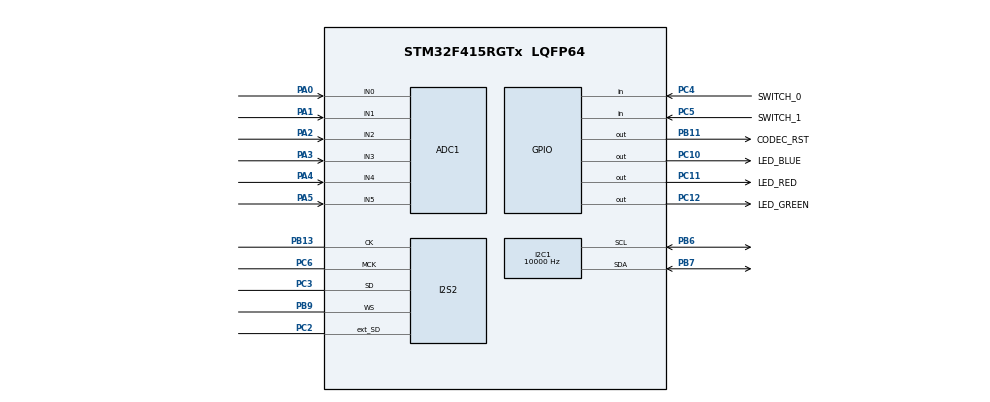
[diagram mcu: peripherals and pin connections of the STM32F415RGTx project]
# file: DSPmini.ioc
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ADC1.Channel-0\#ChannelRegularConversion=ADC_CHANNEL_0
ADC1.Channel-10\#ChannelRegularConversion=ADC_CHANNEL_5
ADC1.Channel-6\#ChannelRegularConversion=ADC_CHANNEL_1
ADC1.Channel-7\#ChannelRegularConversion=ADC_CHANNEL_2
ADC1.Channel-8\#ChannelRegularConversion=ADC_CHANNEL_3
ADC1.Channel-9\#ChannelRegularConversion=ADC_CHANNEL_4
ADC1.ClockPrescaler=ADC_CLOCK_SYNC_PCLK_DIV8
ADC1.ContinuousConvMode=DISABLE
ADC1.DMAContinuousRequests=ENABLE
ADC1.DiscontinuousConvMode=DISABLE
ADC1.EOCSelection=ADC_EOC_SEQ_CONV
ADC1.ExternalTrigConv=ADC_EXTERNALTRIGCONV_T2_TRGO
ADC1.InjNumberOfConversion=0
ADC1.NbrOfConversion=6
ADC1.NbrOfConversionFlag=1
ADC1.Rank-0\#ChannelRegularConversion=1
ADC1.Rank-10\#ChannelRegularConversion=6
ADC1.Rank-6\#ChannelRegularConversion=2
ADC1.Rank-7\#ChannelRegularConversion=3
ADC1.Rank-8\#ChannelRegularConversion=4
ADC1.Rank-9\#ChannelRegularConversion=5
ADC1.SamplingTime-0\#ChannelRegularConversion=ADC_SAMPLETIME_84CYCLES
ADC1.SamplingTime-10\#ChannelRegularConversion=ADC_SAMPLETIME_84CYCLES
ADC1.SamplingTime-6\#ChannelRegularConversion=ADC_SAMPLETIME_84CYCLES
ADC1.SamplingTime-7\#ChannelRegularConversion=ADC_SAMPLETIME_84CYCLES
ADC1.SamplingTime-8\#ChannelRegularConversion=ADC_SAMPLETIME_84CYCLES
ADC1.SamplingTime-9\#ChannelRegularConversion=ADC_SAMPLETIME_84CYCLES
ADC1.ScanConvMode=ENABLE
ADC1.master=1
Dma.ADC1.0.Direction=DMA_PERIPH_TO_MEMORY
Dma.ADC1.0.FIFOMode=DMA_FIFOMODE_DISABLE
Dma.ADC1.0.Instance=DMA2_Stream0
Dma.ADC1.0.MemDataAlignment=DMA_MDATAALIGN_HALFWORD
Dma.ADC1.0.MemInc=DMA_MINC_ENABLE
Dma.ADC1.0.Mode=DMA_CIRCULAR
Dma.ADC1.0.PeriphDataAlignment=DMA_PDATAALIGN_HALFWORD
Dma.ADC1.0.PeriphInc=DMA_PINC_DISABLE
Dma.ADC1.0.Priority=DMA_PRIORITY_MEDIUM
Dma.I2S2_EXT_RX.2.Direction=DMA_PERIPH_TO_MEMORY
Dma.I2S2_EXT_RX.2.FIFOMode=DMA_FIFOMODE_DISABLE
Dma.I2S2_EXT_RX.2.Instance=DMA1_Stream3
Dma.I2S2_EXT_RX.2.MemDataAlignment=DMA_MDATAALIGN_HALFWORD
Dma.I2S2_EXT_RX.2.MemInc=DMA_MINC_ENABLE
Dma.I2S2_EXT_RX.2.Mode=DMA_CIRCULAR
Dma.I2S2_EXT_RX.2.PeriphDataAlignment=DMA_PDATAALIGN_HALFWORD
Dma.I2S2_EXT_RX.2.PeriphInc=DMA_PINC_DISABLE
Dma.I2S2_EXT_RX.2.Priority=DMA_PRIORITY_VERY_HIGH
Dma.Request0=ADC1
Dma.Request1=SPI2_TX
Dma.Request2=I2S2_EXT_RX
Dma.SPI2_TX.1.Direction=DMA_MEMORY_TO_PERIPH
Dma.SPI2_TX.1.FIFOMode=DMA_FIFOMODE_DISABLE
Dma.SPI2_TX.1.Instance=DMA1_Stream4
Dma.SPI2_TX.1.MemDataAlignment=DMA_MDATAALIGN_HALFWORD
Dma.SPI2_TX.1.MemInc=DMA_MINC_ENABLE
Dma.SPI2_TX.1.Mode=DMA_CIRCULAR
Dma.SPI2_TX.1.PeriphDataAlignment=DMA_PDATAALIGN_HALFWORD
Dma.SPI2_TX.1.PeriphInc=DMA_PINC_DISABLE
Dma.SPI2_TX.1.Priority=DMA_PRIORITY_VERY_HIGH
I2C1.ClockSpeed=10000
I2S2.AudioFreq=I2S_AUDIOFREQ_48K
I2S2.ErrorAudioFreq=-2.34 %
I2S2.FullDuplexMode=I2S_FULLDUPLEXMODE_ENABLE
I2S2.Instance=SPI$Index
I2S2.RealAudioFreq=46.875 KHz
I2S2.VirtualMode=I2S_MODE_MASTER
Mcu.Family=STM32F4
Mcu.Name=STM32F415RGTx
Mcu.Package=LQFP64
NVIC.DMA1_Stream3_IRQn=true\:0\:0\:false\:false\:true\:false\:true\:true
NVIC.DMA1_Stream4_IRQn=true\:0\:0\:false\:false\:true\:false\:true\:true
NVIC.DMA2_Stream0_IRQn=true\:0\:0\:false\:false\:true\:false\:true\:true
NVIC.PriorityGroup=NVIC_PRIORITYGROUP_4
NVIC.TIM3_IRQn=true\:0\:0\:false\:false\:true\:true\:true\:true
PA0-WKUP.Signal=ADCx_IN0
PA1.Signal=ADCx_IN1
PA13.Mode=Serial_Wire
PA13.Signal=SYS_JTMS-SWDIO
PA14.Mode=Serial_Wire
PA14.Signal=SYS_JTCK-SWCLK
PA2.Signal=ADCx_IN2
PA3.Signal=ADCx_IN3
PA4.Signal=ADCx_IN4
PA5.Signal=ADCx_IN5
PB11.GPIO_Label=CODEC_RST
PB11.Signal=GPIO_Output
PB13.Mode=Full_Duplex_Master
PB13.Signal=I2S2_CK
PB6.Mode=I2C
PB6.Signal=I2C1_SCL
PB7.Mode=I2C
PB7.Signal=I2C1_SDA
PB9.Mode=Full_Duplex_Master
PB9.Signal=I2S2_WS
PC10.GPIO_Label=LED_BLUE
PC10.Signal=GPIO_Output
PC11.GPIO_Label=LED_RED
PC11.Signal=GPIO_Output
PC12.GPIO_Label=LED_GREEN
PC12.Signal=GPIO_Output
PC2.Mode=Full_Duplex_Master
PC2.Signal=I2S2_ext_SD
PC3.Mode=Full_Duplex_Master
PC3.Signal=I2S2_SD
PC4.GPIO_Label=SWITCH_0
PC4.Signal=GPIO_Input
PC5.GPIO_Label=SWITCH_1
PC5.Signal=GPIO_Input
PC6.Mode=Master_Clock_Activated
PC6.Signal=I2S2_MCK
ProjectManager.HeapSize=0x200
ProjectManager.StackSize=0x400
ProjectManager.TargetToolchain=STM32CubeIDE
RCC.AHBFreq_Value=16000000
RCC.APB1Freq_Value=16000000
RCC.APB2Freq_Value=16000000
RCC.CortexFreq_Value=16000000
RCC.HSE_VALUE=25000000
RCC.HSI_VALUE=16000000
RCC.LSE_VALUE=32768
RCC.SYSCLKFreq_VALUE=16000000
RCC.VCOOutputFreq_Value=192000000
SH.ADCx_IN0.0=ADC1_IN0,IN0
SH.ADCx_IN1.0=ADC1_IN1,IN1
SH.ADCx_IN2.0=ADC1_IN2,IN2
SH.ADCx_IN3.0=ADC1_IN3,IN3
SH.ADCx_IN4.0=ADC1_IN4,IN4
SH.ADCx_IN5.0=ADC1_IN5,IN5
TIM2.AutoReloadPreload=TIM_AUTORELOAD_PRELOAD_ENABLE
TIM2.Period=49999
TIM2.Prescaler=31
TIM2.TIM_MasterOutputTrigger=TIM_TRGO_UPDATE
TIM3.TIM_MasterOutputTrigger=TIM_TRGO_UPDATE
VP_TIM2_VS_ClockSourceINT.Mode=Internal
VP_TIM3_VS_ClockSourceINT.Mode=Internal
board=custom

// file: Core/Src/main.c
/* USER CODE BEGIN Header */
/**
  ******************************************************************************
  * @file           : main.c
  * @brief          : Main program body
  ******************************************************************************
  * @attention
  *
  * Copyright (c) 2024 STMicroelectronics.
  * All rights reserved.
  *
  * This software is licensed under terms that can be found in the LICENSE file
  * in the root directory of this software component.
  * If no LICENSE file comes with this software, it is provided AS-IS.
  *
  ******************************************************************************
  */
/* USER CODE END Header */
#include "main.h"

/* USER CODE BEGIN Includes */
#include "codec.h"
#include "IIR_PeakingFilter.h"
/* USER CODE END Includes */

/* USER CODE BEGIN PD */
#define NUM_ADC_CHANNELS 	6
#define AUDIO_BUFFER_SIZE	64

#define SAMPLE_RATE_HZ		46875.0f	//will change when osc is fitted to board

#define UINT16_TO_FLOAT 0.00001525878f
#define INT16_TO_FLOAT 0.00003051757f
#define FLOAT_TO_INT16 32768.0f

#define BASS_EQ_FREQ	150.0f
#define MID_EQ_FREQ		450.0f
#define HIGH_EQ_FREQ	5000.0f
/* USER CODE END PD */

ADC_HandleTypeDef hadc1;
DMA_HandleTypeDef hdma_adc1;

I2C_HandleTypeDef hi2c1;

I2S_HandleTypeDef hi2s2;
DMA_HandleTypeDef hdma_spi2_tx;
DMA_HandleTypeDef hdma_i2s2_ext_rx;

TIM_HandleTypeDef htim2;
TIM_HandleTypeDef htim3;

/* USER CODE BEGIN PV */

uint16_t adcData[NUM_ADC_CHANNELS];	//buffer for the ADC data from the ADC used to read the potentiometers

static int16_t codecInData[AUDIO_BUFFER_SIZE];	//buffers to deal with the in/out of the codec
static int16_t codecOutData[AUDIO_BUFFER_SIZE];

volatile uint8_t audioDataReadyFlag = 0;
volatile uint8_t audio_update_lockout_flag = 0;

static volatile int16_t *codecInBuff_p;	//pointers to help handle the double buffering (read half and process the other half at the same time) of the CODEC data
static volatile int16_t *codecOutBuff_p;
//structure to hold all the ADC values from the pots
struct potentiometers
{
	uint16_t pot1;
	uint16_t pot2;
	uint16_t pot3;
	uint16_t pot4;
	uint16_t pot5;
	uint16_t pot6;
}pots;

IIR_peakingFilter bass_filter;
IIR_peakingFilter mid_filter;
IIR_peakingFilter high_filter;
/* USER CODE END PV */

void SystemClock_Config(void);
static void MX_GPIO_Init(void);
static void MX_DMA_Init(void);
static void MX_ADC1_Init(void);
static void MX_I2C1_Init(void);
static void MX_I2S2_Init(void);
static void MX_TIM2_Init(void);
static void MX_TIM3_Init(void);
/* USER CODE BEGIN PFP */
void update_filter_settings(uint16_t q_pot, uint16_t boostCut_pot, IIR_peakingFilter *filt, float centre_freq);
/* USER CODE END PFP */

/* USER CODE BEGIN 0 */

//this function is called every time an ADC conversion is complete
void HAL_ADC_ConvCpltCallback(ADC_HandleTypeDef *hadc)
{
	//HAL_GPIO_TogglePin(LED_GREEN_GPIO_Port, LED_GREEN_Pin);

	//unload the array into our structure for easier handling
	pots.pot1 = adcData[0];
	pots.pot2 = adcData[1];
	pots.pot3 = adcData[4];
	pots.pot4 = adcData[5];
	pots.pot5 = adcData[2];
	pots.pot6 = adcData[3];

	update_filter_settings(pots.pot1, pots.pot2, &bass_filter, BASS_EQ_FREQ);
	update_filter_settings(pots.pot3, pots.pot4, &mid_filter, MID_EQ_FREQ);
	update_filter_settings(pots.pot5, pots.pot6, &high_filter, HIGH_EQ_FREQ);
}

void update_filter_settings(uint16_t q_pot, uint16_t boostCut_pot, IIR_peakingFilter *filt, float centre_freq)
{
	//convert pot values to something in range for our filters
	//max ADC = 4096
	//205 (approx) for a 20 bit scaling
	float Q, boostCut;

	Q = q_pot / 205;
	boostCut = boostCut_pot / 205;

	if(!audio_update_lockout_flag)
	{
		IIR_peakingFilter_setParams(filt, centre_freq, Q, boostCut);
	}

}

//function is called when I2S data is half complete, so align the pointers to the first half of the buffers
void HAL_I2SEx_TxRxHalfCpltCallback(I2S_HandleTypeDef *hi2s)
{
	codecInBuff_p = &codecInData[0];
	codecOutBuff_p = &codecOutData[0];

	audioDataReadyFlag = 1;
}

//function is called when I2S data is complete, so align the pointers to the second half of the buffers
void HAL_I2SEx_TxRxCpltCallback(I2S_HandleTypeDef *hi2s)
{
	codecInBuff_p = &codecInData[AUDIO_BUFFER_SIZE/2];
	codecOutBuff_p = &codecOutData[AUDIO_BUFFER_SIZE/2];

	audioDataReadyFlag = 1;
}

void processData(void)
{
	static float leftIn, leftOut; //, rightIn, rightOut;

	audio_update_lockout_flag = 1;

	for(uint8_t n = 0; n < (AUDIO_BUFFER_SIZE/2) - 1; n += 2)
	{

	//	codecOutBuff_p[n] = codecInBuff_p[n];	//debug
		//left channel data
		leftIn = INT16_TO_FLOAT * ((float) codecInBuff_p[n]);

		if(leftIn > 1.0f)
		{
			leftIn -= 2.0f;	//make sure data is within 1/-1
		}

		//modify the data here
		leftOut = IIR_peakingFilter_update(&bass_filter, leftIn);
		leftOut = IIR_peakingFilter_update(&mid_filter, leftOut);
	//	leftOut = IIR_peakingFilter_update(&high_filter, leftOut);
		//leftOut = leftIn; //debug

		//convert back to signed int and transfer to DAC (via pointer)
		codecOutBuff_p[n] =  (int16_t) (FLOAT_TO_INT16 * leftOut);

		//////////////////////
		//right channel data (not used in current hardware)
	/*	rightIn = (float)codecInBuff_p[n+1];

		if(rightIn > 1.0f)
		{
			rightIn -= 2.0f;	//make sure data is within 1/-1
		}

		//modify the data here
		rightOut = rightIn;

		//convert back to signed int and transfer to DAC (via pointer)
		codecOutBuff_p[n] = (int16_t) rightOut;
*/
	}

	audio_update_lockout_flag = 0;
	audioDataReadyFlag = 0;
}

/* USER CODE END 0 */

int main(void)
{

  /* MCU Configuration--------------------------------------------------------*/

  /* Reset of all peripherals, Initializes the Flash interface and the Systick. */
  HAL_Init();

  /* Configure the system clock */
  SystemClock_Config();

  /* Initialize all configured peripherals */
  MX_GPIO_Init();
  MX_DMA_Init();
  MX_ADC1_Init();
  MX_I2C1_Init();
  MX_I2S2_Init();
  MX_TIM2_Init();
  MX_TIM3_Init();
  /* USER CODE BEGIN 2 */

  HAL_ADC_Start_DMA(&hadc1, (uint32_t *) adcData, NUM_ADC_CHANNELS); 	//start the ADC and link it with the DMA
  HAL_TIM_Base_Start(&htim2); 											//start timer 2 which triggers the ADC
  HAL_I2SEx_TransmitReceive_DMA(&hi2s2, (uint16_t *) codecOutData, (uint16_t *) codecInData, AUDIO_BUFFER_SIZE);
  codec_hardware_reset_pin_clear();
  HAL_Delay(50);
  codec_configure(&hi2c1);
  IIR_peakingFilter_init(&bass_filter, SAMPLE_RATE_HZ);		//initialise bass frequency peaking filter
  IIR_peakingFilter_init(&mid_filter, SAMPLE_RATE_HZ);
  IIR_peakingFilter_init(&high_filter, SAMPLE_RATE_HZ);
  /* USER CODE END 2 */

  /* Infinite loop */
  /* USER CODE BEGIN WHILE */
  while (1)
  {
	  if(audioDataReadyFlag)
	  {
		  processData();
	  }
/*	  if(HAL_GPIO_ReadPin(GPIOC, GPIO_PIN_4))		//switch 0
	  {
		  HAL_GPIO_TogglePin(GPIOC, GPIO_PIN_10);	//Blue
		  HAL_GPIO_TogglePin(GPIOC, GPIO_PIN_11);	//Red
		  HAL_Delay(500);
	  }

	  if(HAL_GPIO_ReadPin(SWITCH_1_GPIO_Port, SWITCH_1_Pin))
	  {
		  HAL_GPIO_TogglePin(LED_GREEN_GPIO_Port, LED_GREEN_Pin);
		  HAL_Delay(500);
	  }
*/
    /* USER CODE END WHILE */

  }
}

void SystemClock_Config(void)
{
  RCC_OscInitTypeDef RCC_OscInitStruct = {0};
  RCC_ClkInitTypeDef RCC_ClkInitStruct = {0};

  /** Configure the main internal regulator output voltage
  */
  __HAL_RCC_PWR_CLK_ENABLE();
  __HAL_PWR_VOLTAGESCALING_CONFIG(PWR_REGULATOR_VOLTAGE_SCALE1);

  /** Initializes the RCC Oscillators according to the specified parameters
  * in the RCC_OscInitTypeDef structure.
  */
  RCC_OscInitStruct.OscillatorType = RCC_OSCILLATORTYPE_HSI;
  RCC_OscInitStruct.HSIState = RCC_HSI_ON;
  RCC_OscInitStruct.HSICalibrationValue = RCC_HSICALIBRATION_DEFAULT;
  RCC_OscInitStruct.PLL.PLLState = RCC_PLL_ON;
  RCC_OscInitStruct.PLL.PLLSource = RCC_PLLSOURCE_HSI;
  RCC_OscInitStruct.PLL.PLLM = 16;
  RCC_OscInitStruct.PLL.PLLN = 192;
  RCC_OscInitStruct.PLL.PLLP = RCC_PLLP_DIV2;
  RCC_OscInitStruct.PLL.PLLQ = 4;
  if (HAL_RCC_OscConfig(&RCC_OscInitStruct) != HAL_OK)
  {
    Error_Handler();
  }

  /** Initializes the CPU, AHB and APB buses clocks
  */
  RCC_ClkInitStruct.ClockType = RCC_CLOCKTYPE_HCLK|RCC_CLOCKTYPE_SYSCLK
                              |RCC_CLOCKTYPE_PCLK1|RCC_CLOCKTYPE_PCLK2;
  RCC_ClkInitStruct.SYSCLKSource = RCC_SYSCLKSOURCE_PLLCLK;
  RCC_ClkInitStruct.AHBCLKDivider = RCC_SYSCLK_DIV1;
  RCC_ClkInitStruct.APB1CLKDivider = RCC_HCLK_DIV4;
  RCC_ClkInitStruct.APB2CLKDivider = RCC_HCLK_DIV8;

  if (HAL_RCC_ClockConfig(&RCC_ClkInitStruct, FLASH_LATENCY_3) != HAL_OK)
  {
    Error_Handler();
  }
}

static void MX_ADC1_Init(void)
{

  ADC_ChannelConfTypeDef sConfig = {0};

  /** Configure the global features of the ADC (Clock, Resolution, Data Alignment and number of conversion)
  */
  hadc1.Instance = ADC1;
  hadc1.Init.ClockPrescaler = ADC_CLOCK_SYNC_PCLK_DIV8;
  hadc1.Init.Resolution = ADC_RESOLUTION_12B;
  hadc1.Init.ScanConvMode = ENABLE;
  hadc1.Init.ContinuousConvMode = DISABLE;
  hadc1.Init.DiscontinuousConvMode = DISABLE;
  hadc1.Init.ExternalTrigConvEdge = ADC_EXTERNALTRIGCONVEDGE_RISING;
  hadc1.Init.ExternalTrigConv = ADC_EXTERNALTRIGCONV_T2_TRGO;
  hadc1.Init.DataAlign = ADC_DATAALIGN_RIGHT;
  hadc1.Init.NbrOfConversion = 6;
  hadc1.Init.DMAContinuousRequests = ENABLE;
  hadc1.Init.EOCSelection = ADC_EOC_SEQ_CONV;
  if (HAL_ADC_Init(&hadc1) != HAL_OK)
  {
    Error_Handler();
  }

  /** Configure for the selected ADC regular channel its corresponding rank in the sequencer and its sample time.
  */
  sConfig.Channel = ADC_CHANNEL_0;
  sConfig.Rank = 1;
  sConfig.SamplingTime = ADC_SAMPLETIME_84CYCLES;
  if (HAL_ADC_ConfigChannel(&hadc1, &sConfig) != HAL_OK)
  {
    Error_Handler();
  }

  /** Configure for the selected ADC regular channel its corresponding rank in the sequencer and its sample time.
  */
  sConfig.Channel = ADC_CHANNEL_1;
  sConfig.Rank = 2;
  if (HAL_ADC_ConfigChannel(&hadc1, &sConfig) != HAL_OK)
  {
    Error_Handler();
  }

  /** Configure for the selected ADC regular channel its corresponding rank in the sequencer and its sample time.
  */
  sConfig.Channel = ADC_CHANNEL_2;
  sConfig.Rank = 3;
  if (HAL_ADC_ConfigChannel(&hadc1, &sConfig) != HAL_OK)
  {
    Error_Handler();
  }

  /** Configure for the selected ADC regular channel its corresponding rank in the sequencer and its sample time.
  */
  sConfig.Channel = ADC_CHANNEL_3;
  sConfig.Rank = 4;
  if (HAL_ADC_ConfigChannel(&hadc1, &sConfig) != HAL_OK)
  {
    Error_Handler();
  }

  /** Configure for the selected ADC regular channel its corresponding rank in the sequencer and its sample time.
  */
  sConfig.Channel = ADC_CHANNEL_4;
  sConfig.Rank = 5;
  if (HAL_ADC_ConfigChannel(&hadc1, &sConfig) != HAL_OK)
  {
    Error_Handler();
  }

  /** Configure for the selected ADC regular channel its corresponding rank in the sequencer and its sample time.
  */
  sConfig.Channel = ADC_CHANNEL_5;
  sConfig.Rank = 6;
  if (HAL_ADC_ConfigChannel(&hadc1, &sConfig) != HAL_OK)
  {
    Error_Handler();
  }

}

static void MX_I2C1_Init(void)
{

  hi2c1.Instance = I2C1;
  hi2c1.Init.ClockSpeed = 10000;
  hi2c1.Init.DutyCycle = I2C_DUTYCYCLE_2;
  hi2c1.Init.OwnAddress1 = 0;
  hi2c1.Init.AddressingMode = I2C_ADDRESSINGMODE_7BIT;
  hi2c1.Init.DualAddressMode = I2C_DUALADDRESS_DISABLE;
  hi2c1.Init.OwnAddress2 = 0;
  hi2c1.Init.GeneralCallMode = I2C_GENERALCALL_DISABLE;
  hi2c1.Init.NoStretchMode = I2C_NOSTRETCH_DISABLE;
  if (HAL_I2C_Init(&hi2c1) != HAL_OK)
  {
    Error_Handler();
  }

}

static void MX_I2S2_Init(void)
{

  hi2s2.Instance = SPI2;
  hi2s2.Init.Mode = I2S_MODE_MASTER_TX;
  hi2s2.Init.Standard = I2S_STANDARD_PHILIPS;
  hi2s2.Init.DataFormat = I2S_DATAFORMAT_16B;
  hi2s2.Init.MCLKOutput = I2S_MCLKOUTPUT_ENABLE;
  hi2s2.Init.AudioFreq = I2S_AUDIOFREQ_48K;
  hi2s2.Init.CPOL = I2S_CPOL_LOW;
  hi2s2.Init.ClockSource = I2S_CLOCK_PLL;
  hi2s2.Init.FullDuplexMode = I2S_FULLDUPLEXMODE_ENABLE;
  if (HAL_I2S_Init(&hi2s2) != HAL_OK)
  {
    Error_Handler();
  }

}

static void MX_TIM2_Init(void)
{

  TIM_ClockConfigTypeDef sClockSourceConfig = {0};
  TIM_MasterConfigTypeDef sMasterConfig = {0};

  htim2.Instance = TIM2;
  htim2.Init.Prescaler = 31;
  htim2.Init.CounterMode = TIM_COUNTERMODE_UP;
  htim2.Init.Period = 49999;
  htim2.Init.ClockDivision = TIM_CLOCKDIVISION_DIV1;
  htim2.Init.AutoReloadPreload = TIM_AUTORELOAD_PRELOAD_ENABLE;
  if (HAL_TIM_Base_Init(&htim2) != HAL_OK)
  {
    Error_Handler();
  }
  sClockSourceConfig.ClockSource = TIM_CLOCKSOURCE_INTERNAL;
  if (HAL_TIM_ConfigClockSource(&htim2, &sClockSourceConfig) != HAL_OK)
  {
    Error_Handler();
  }
  sMasterConfig.MasterOutputTrigger = TIM_TRGO_UPDATE;
  sMasterConfig.MasterSlaveMode = TIM_MASTERSLAVEMODE_DISABLE;
  if (HAL_TIMEx_MasterConfigSynchronization(&htim2, &sMasterConfig) != HAL_OK)
  {
    Error_Handler();
  }

}

static void MX_TIM3_Init(void)
{

  TIM_ClockConfigTypeDef sClockSourceConfig = {0};
  TIM_MasterConfigTypeDef sMasterConfig = {0};

  htim3.Instance = TIM3;
  htim3.Init.Prescaler = 0;
  htim3.Init.CounterMode = TIM_COUNTERMODE_UP;
  htim3.Init.Period = 65535;
  htim3.Init.ClockDivision = TIM_CLOCKDIVISION_DIV1;
  htim3.Init.AutoReloadPreload = TIM_AUTORELOAD_PRELOAD_DISABLE;
  if (HAL_TIM_Base_Init(&htim3) != HAL_OK)
  {
    Error_Handler();
  }
  sClockSourceConfig.ClockSource = TIM_CLOCKSOURCE_INTERNAL;
  if (HAL_TIM_ConfigClockSource(&htim3, &sClockSourceConfig) != HAL_OK)
  {
    Error_Handler();
  }
  sMasterConfig.MasterOutputTrigger = TIM_TRGO_UPDATE;
  sMasterConfig.MasterSlaveMode = TIM_MASTERSLAVEMODE_DISABLE;
  if (HAL_TIMEx_MasterConfigSynchronization(&htim3, &sMasterConfig) != HAL_OK)
  {
    Error_Handler();
  }

}

static void MX_DMA_Init(void)
{

  /* DMA controller clock enable */
  __HAL_RCC_DMA2_CLK_ENABLE();
  __HAL_RCC_DMA1_CLK_ENABLE();

  /* DMA interrupt init */
  /* DMA1_Stream3_IRQn interrupt configuration */
  HAL_NVIC_SetPriority(DMA1_Stream3_IRQn, 0, 0);
  HAL_NVIC_EnableIRQ(DMA1_Stream3_IRQn);
  /* DMA1_Stream4_IRQn interrupt configuration */
  HAL_NVIC_SetPriority(DMA1_Stream4_IRQn, 0, 0);
  HAL_NVIC_EnableIRQ(DMA1_Stream4_IRQn);
  /* DMA2_Stream0_IRQn interrupt configuration */
  HAL_NVIC_SetPriority(DMA2_Stream0_IRQn, 0, 0);
  HAL_NVIC_EnableIRQ(DMA2_Stream0_IRQn);

}

static void MX_GPIO_Init(void)
{
  GPIO_InitTypeDef GPIO_InitStruct = {0};

  /* GPIO Ports Clock Enable */
  __HAL_RCC_GPIOC_CLK_ENABLE();
  __HAL_RCC_GPIOA_CLK_ENABLE();
  __HAL_RCC_GPIOB_CLK_ENABLE();

  /*Configure GPIO pin Output Level */
  HAL_GPIO_WritePin(CODEC_RST_GPIO_Port, CODEC_RST_Pin, GPIO_PIN_RESET);

  /*Configure GPIO pin Output Level */
  HAL_GPIO_WritePin(GPIOC, LED_BLUE_Pin|LED_RED_Pin|LED_GREEN_Pin, GPIO_PIN_RESET);

  /*Configure GPIO pins : SWITCH_0_Pin SWITCH_1_Pin */
  GPIO_InitStruct.Pin = SWITCH_0_Pin|SWITCH_1_Pin;
  GPIO_InitStruct.Mode = GPIO_MODE_INPUT;
  GPIO_InitStruct.Pull = GPIO_NOPULL;
  HAL_GPIO_Init(GPIOC, &GPIO_InitStruct);

  /*Configure GPIO pin : CODEC_RST_Pin */
  GPIO_InitStruct.Pin = CODEC_RST_Pin;
  GPIO_InitStruct.Mode = GPIO_MODE_OUTPUT_PP;
  GPIO_InitStruct.Pull = GPIO_NOPULL;
  GPIO_InitStruct.Speed = GPIO_SPEED_FREQ_LOW;
  HAL_GPIO_Init(CODEC_RST_GPIO_Port, &GPIO_InitStruct);

  /*Configure GPIO pins : LED_BLUE_Pin LED_RED_Pin LED_GREEN_Pin */
  GPIO_InitStruct.Pin = LED_BLUE_Pin|LED_RED_Pin|LED_GREEN_Pin;
  GPIO_InitStruct.Mode = GPIO_MODE_OUTPUT_PP;
  GPIO_InitStruct.Pull = GPIO_NOPULL;
  GPIO_InitStruct.Speed = GPIO_SPEED_FREQ_LOW;
  HAL_GPIO_Init(GPIOC, &GPIO_InitStruct);

}

void Error_Handler(void)
{
  __disable_irq();
  while (1)
  {
  }
}
